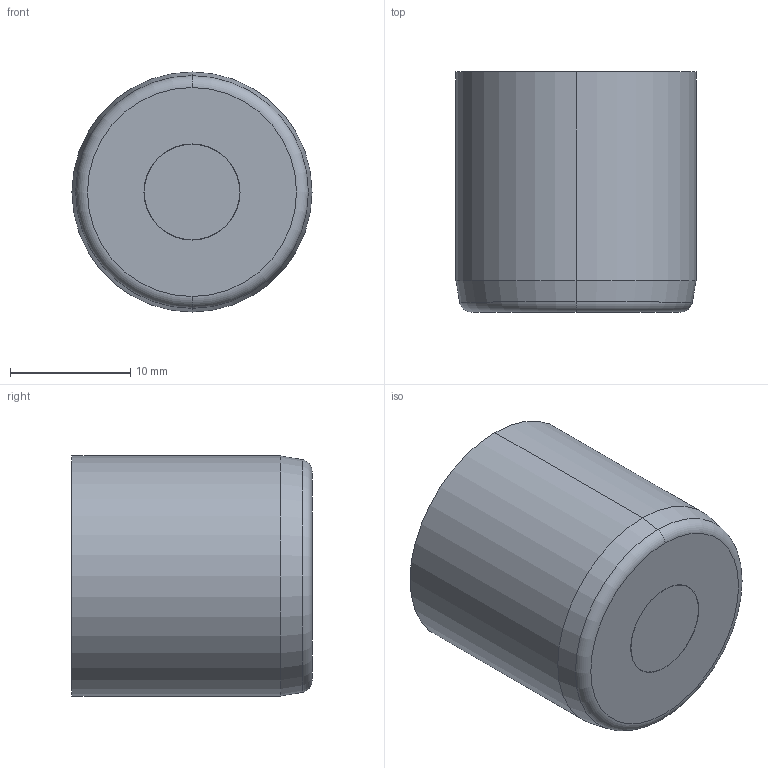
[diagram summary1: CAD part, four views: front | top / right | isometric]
STEP (ISO 10303-21) file: header records copied from the file, then geometry measured from it (millimetres).
FILE_DESCRIPTION (( 'STEP AP214' ), '1' );
FILE_NAME ('FA 200712-20.STEP', '2013-10-01T10:25:38', ( '' ), ( '' ), 'SwSTEP 2.0', 'SolidWorks 2011', '' );
FILE_SCHEMA (( 'AUTOMOTIVE_DESIGN' ));
Length unit declared in the file: millimetre
Products named in the file (6): 9FA 042212; IA 100720; FA 168700-2 comprimido; FA 168700-3; FA 168700-1; FA 200712-20
Assembly tree (5 placements, depth 2):
  FA 200712-20
    FA 168700-1
    IA 100720
    FA 168700-3
    9FA 042212
    FA 168700-2 comprimido
Bounding box: 20 x 20 x 20 mm (x, y, z)
Volume: 6007.1 mm3; surface area: 3298.7 mm2
Topology: 5 solids, 5 shells, 331 faces, 838 edges, 545 vertices
Faces by surface type: plane 145, cylinder 140, cone 34, torus 10, bspline 2
Entity records: 11560 total; most frequent: CARTESIAN_POINT 3046, DIRECTION 1812, ORIENTED_EDGE 1672, EDGE_CURVE 836, AXIS2_PLACEMENT_3D 671, VERTEX_POINT 545, VECTOR 470, LINE 470
One B-rep face of a CAD part: STEP entity #6858.
In plain terms, the cylindrical face has radius 10 mm (diameter 20 mm), a partial arc.
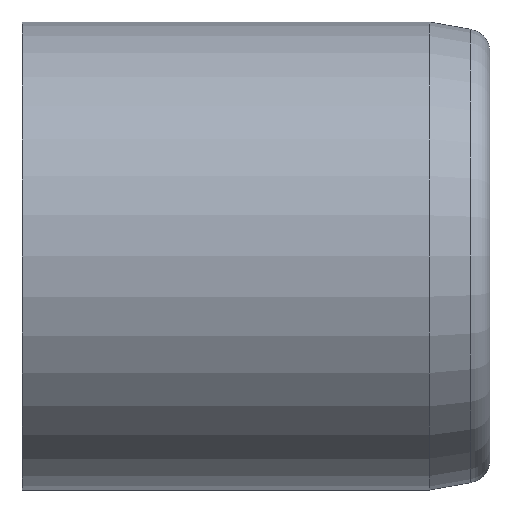
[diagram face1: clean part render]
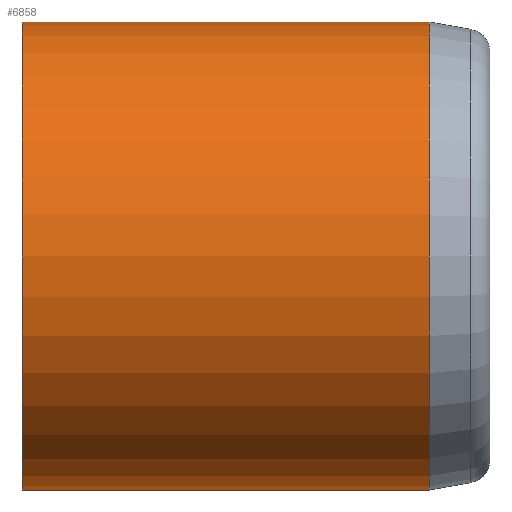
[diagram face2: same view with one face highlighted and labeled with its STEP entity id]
Its self-contained STEP definition (entity closure, numbers rounded to 3 decimals):
#177 = VERTEX_POINT ( 'NONE', #10033 ) ;
#184 = VERTEX_POINT ( 'NONE', #10034 ) ;
#218 = VERTEX_POINT ( 'NONE', #10134 ) ;
#219 = VERTEX_POINT ( 'NONE', #10122 ) ;
#436 = ORIENTED_EDGE ( 'NONE', *, *, #9428, .T. ) ;
#467 = ORIENTED_EDGE ( 'NONE', *, *, #7819, .T. ) ;
#491 = ORIENTED_EDGE ( 'NONE', *, *, #7811, .F. ) ;
#502 = ORIENTED_EDGE ( 'NONE', *, *, #7805, .F. ) ;
#1888 = CIRCLE ( 'NONE', #1924, 10. ) ;
#1924 = AXIS2_PLACEMENT_3D ( 'NONE', #5579, #5580, #5557 ) ;
#2009 = CIRCLE ( 'NONE', #2012, 10. ) ;
#2012 = AXIS2_PLACEMENT_3D ( 'NONE', #5512, #5521, #5542 ) ;
#2024 = VECTOR ( 'NONE', #5575, 1000. ) ;
#2239 = CARTESIAN_POINT ( 'NONE',  ( 0., -9.8, 10. ) ) ;
#2241 = DIRECTION ( 'NONE',  ( 0., 1., 0. ) ) ;
#2257 = LINE ( 'NONE', #2239, #3208 ) ;
#3208 = VECTOR ( 'NONE', #2241, 1000. ) ;
#5512 = CARTESIAN_POINT ( 'NONE',  ( 0., 2.73, 0. ) ) ;
#5521 = DIRECTION ( 'NONE',  ( 0., -1., 0. ) ) ;
#5536 = LINE ( 'NONE', #5546, #2024 ) ;
#5542 = DIRECTION ( 'NONE',  ( 0., 0., -1. ) ) ;
#5546 = CARTESIAN_POINT ( 'NONE',  ( 0., -9.8, -10. ) ) ;
#5557 = DIRECTION ( 'NONE',  ( 0., 0., 1. ) ) ;
#5575 = DIRECTION ( 'NONE',  ( 0., 1., 0. ) ) ;
#5579 = CARTESIAN_POINT ( 'NONE',  ( 0., 20.13, 0. ) ) ;
#5580 = DIRECTION ( 'NONE',  ( 0., -1., 0. ) ) ;
#6194 = AXIS2_PLACEMENT_3D ( 'NONE', #10662, #10702, #10664 ) ;
#6858 = ADVANCED_FACE ( 'NONE', ( #10715 ), #10701, .T. ) ;
#7805 = EDGE_CURVE ( 'NONE', #218, #184, #2009, .T. ) ;
#7811 = EDGE_CURVE ( 'NONE', #184, #219, #5536, .T. ) ;
#7819 = EDGE_CURVE ( 'NONE', #177, #219, #1888, .T. ) ;
#9428 = EDGE_CURVE ( 'NONE', #218, #177, #2257, .T. ) ;
#9834 = EDGE_LOOP ( 'NONE', ( #491, #502, #436, #467 ) ) ;
#10033 = CARTESIAN_POINT ( 'NONE',  ( 0., 20.13, 10. ) ) ;
#10034 = CARTESIAN_POINT ( 'NONE',  ( 0., 2.73, -10. ) ) ;
#10122 = CARTESIAN_POINT ( 'NONE',  ( 0., 20.13, -10. ) ) ;
#10134 = CARTESIAN_POINT ( 'NONE',  ( 0., 2.73, 10. ) ) ;
#10662 = CARTESIAN_POINT ( 'NONE',  ( 0., -9.8, 0. ) ) ;
#10664 = DIRECTION ( 'NONE',  ( 0., 0., 1. ) ) ;
#10701 = CYLINDRICAL_SURFACE ( 'NONE', #6194, 10. ) ;
#10702 = DIRECTION ( 'NONE',  ( 0., 1., 0. ) ) ;
#10715 = FACE_OUTER_BOUND ( 'NONE', #9834, .T. ) ;
